One B-rep face of a CAD part: STEP entity #11.
In plain terms, the planar face has unit normal (1, 0, 0).
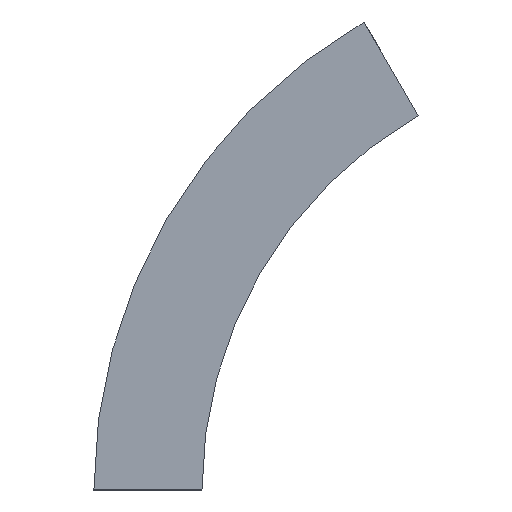
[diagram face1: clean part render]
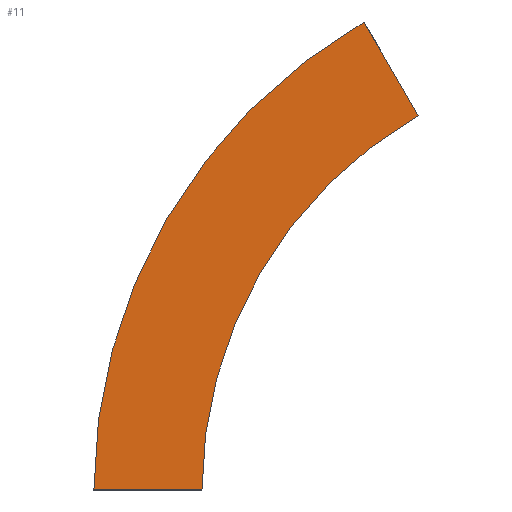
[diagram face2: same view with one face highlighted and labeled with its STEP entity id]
Its self-contained STEP definition (entity closure, numbers rounded to 3 decimals):
#11 = ADVANCED_FACE ( 'NONE', ( #317 ), #499, .T. ) ;
#16 = VERTEX_POINT ( 'NONE', #20 ) ;
#20 = CARTESIAN_POINT ( 'NONE',  ( 0., 0., 0. ) ) ;
#23 = DIRECTION ( 'NONE',  ( 1., 0., 0. ) ) ;
#28 = DIRECTION ( 'NONE',  ( 0., 1., 0. ) ) ;
#54 = AXIS2_PLACEMENT_3D ( 'NONE', #102, #196, #547 ) ;
#56 = DIRECTION ( 'NONE',  ( 0., 1., 0. ) ) ;
#74 = AXIS2_PLACEMENT_3D ( 'NONE', #405, #306, #403 ) ;
#82 = VECTOR ( 'NONE', #56, 1000. ) ;
#95 = CIRCLE ( 'NONE', #74, 375. ) ;
#101 = CIRCLE ( 'NONE', #439, 300. ) ;
#102 = CARTESIAN_POINT ( 'NONE',  ( 0., 0., 0. ) ) ;
#137 = CARTESIAN_POINT ( 'NONE',  ( 0., 75., 0. ) ) ;
#165 = EDGE_CURVE ( 'NONE', #16, #327, #101, .T. ) ;
#179 = LINE ( 'NONE', #182, #315 ) ;
#182 = CARTESIAN_POINT ( 'NONE',  ( 0., -150., 259.808 ) ) ;
#186 = CARTESIAN_POINT ( 'NONE',  ( 0., -150., 259.808 ) ) ;
#190 = ORIENTED_EDGE ( 'NONE', *, *, #326, .T. ) ;
#196 = DIRECTION ( 'NONE',  ( 1., 0., 0. ) ) ;
#222 = VERTEX_POINT ( 'NONE', #137 ) ;
#237 = VERTEX_POINT ( 'NONE', #558 ) ;
#241 = CARTESIAN_POINT ( 'NONE',  ( 0., -300., 0. ) ) ;
#261 = EDGE_LOOP ( 'NONE', ( #190, #536, #274, #312 ) ) ;
#274 = ORIENTED_EDGE ( 'NONE', *, *, #165, .F. ) ;
#290 = EDGE_CURVE ( 'NONE', #327, #237, #179, .T. ) ;
#306 = DIRECTION ( 'NONE',  ( 1., 0., 0. ) ) ;
#312 = ORIENTED_EDGE ( 'NONE', *, *, #364, .T. ) ;
#315 = VECTOR ( 'NONE', #523, 1000. ) ;
#317 = FACE_OUTER_BOUND ( 'NONE', #261, .T. ) ;
#324 = LINE ( 'NONE', #545, #82 ) ;
#326 = EDGE_CURVE ( 'NONE', #222, #237, #95, .T. ) ;
#327 = VERTEX_POINT ( 'NONE', #186 ) ;
#364 = EDGE_CURVE ( 'NONE', #16, #222, #324, .T. ) ;
#403 = DIRECTION ( 'NONE',  ( 0., 1., 0. ) ) ;
#405 = CARTESIAN_POINT ( 'NONE',  ( 0., -300., 0. ) ) ;
#439 = AXIS2_PLACEMENT_3D ( 'NONE', #241, #23, #28 ) ;
#499 = PLANE ( 'NONE',  #54 ) ;
#523 = DIRECTION ( 'NONE',  ( 0., 0.5, 0.866 ) ) ;
#536 = ORIENTED_EDGE ( 'NONE', *, *, #290, .F. ) ;
#545 = CARTESIAN_POINT ( 'NONE',  ( 0., 0., 0. ) ) ;
#547 = DIRECTION ( 'NONE',  ( 0., 0., -1. ) ) ;
#558 = CARTESIAN_POINT ( 'NONE',  ( 0., -112.5, 324.76 ) ) ;
